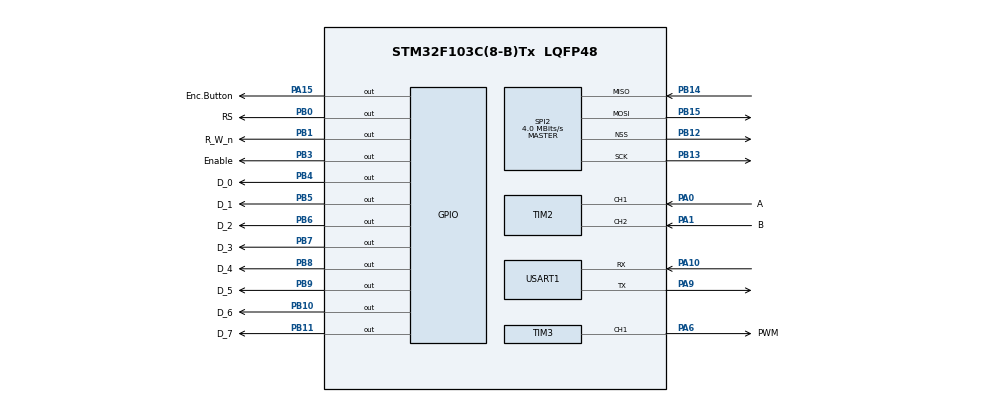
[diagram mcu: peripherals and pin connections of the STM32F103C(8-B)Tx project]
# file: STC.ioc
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Mcu.Family=STM32F1
Mcu.Name=STM32F103C(8-B)Tx
Mcu.Package=LQFP48
NVIC.PriorityGroup=NVIC_PRIORITYGROUP_4
PA0-WKUP.GPIO_Label=A
PA0-WKUP.Signal=S_TIM2_CH1_ETR
PA1.GPIO_Label=B
PA1.Signal=S_TIM2_CH2
PA10.Mode=Asynchronous
PA10.Signal=USART1_RX
PA13.Mode=Serial_Wire
PA13.Signal=SYS_JTMS-SWDIO
PA14.Mode=Serial_Wire
PA14.Signal=SYS_JTCK-SWCLK
PA15.GPIO_Label=Enc.Button
PA15.Signal=GPIO_Output
PA6.GPIO_Label=PWM
PA6.Signal=S_TIM3_CH1
PA9.Mode=Asynchronous
PA9.Signal=USART1_TX
PB0.GPIO_Label=RS
PB0.Signal=GPIO_Output
PB1.GPIO_Label=R_W_n
PB1.Signal=GPIO_Output
PB10.GPIO_Label=D_6
PB10.Signal=GPIO_Output
PB11.GPIO_Label=D_7
PB11.Signal=GPIO_Output
PB12.Mode=NSS_Signal_Hard_Output
PB12.Signal=SPI2_NSS
PB13.Mode=Full_Duplex_Master
PB13.Signal=SPI2_SCK
PB14.Mode=Full_Duplex_Master
PB14.Signal=SPI2_MISO
PB15.Mode=Full_Duplex_Master
PB15.Signal=SPI2_MOSI
PB3.GPIO_Label=Enable
PB3.Signal=GPIO_Output
PB4.GPIO_Label=D_0
PB4.Signal=GPIO_Output
PB5.GPIO_Label=D_1
PB5.Signal=GPIO_Output
PB6.GPIO_Label=D_2
PB6.Signal=GPIO_Output
PB7.GPIO_Label=D_3
PB7.Signal=GPIO_Output
PB8.GPIO_Label=D_4
PB8.Signal=GPIO_Output
PB9.GPIO_Label=D_5
PB9.Signal=GPIO_Output
PD0-OSC_IN.Mode=HSE-External-Clock-Source
PD0-OSC_IN.Signal=RCC_OSC_IN
PD1-OSC_OUT.Mode=HSE-External-Clock-Source
PD1-OSC_OUT.Signal=RCC_OSC_OUT
ProjectManager.HeapSize=0x200
ProjectManager.StackSize=0x400
ProjectManager.TargetToolchain=MDK-ARM V5.27
RCC.APB1Freq_Value=8000000
RCC.APB2Freq_Value=8000000
SH.S_TIM2_CH1_ETR.0=TIM2_CH1,Encoder_Interface
SH.S_TIM2_CH2.0=TIM2_CH2,Encoder_Interface
SH.S_TIM3_CH1.0=TIM3_CH1,PWM Generation1 CH1
SPI2.CalculateBaudRate=4.0 MBits/s
SPI2.Direction=SPI_DIRECTION_2LINES
SPI2.Mode=SPI_MODE_MASTER
SPI2.VirtualNSS=VM_NSSHARD
SPI2.VirtualType=VM_MASTER
TIM2.IC1Filter=10
TIM2.IC1Polarity=TIM_ICPOLARITY_FALLING
TIM2.IC2Filter=10
TIM2.IC2Polarity=TIM_ICPOLARITY_FALLING
TIM3.Channel-PWM\ Generation1\ CH1=TIM_CHANNEL_1
TIM3.Period=10000
TIM3.Prescaler=71
TIM3.Pulse-PWM\ Generation1\ CH1=100
USART1.VirtualMode=VM_ASYNC
VP_TIM3_VS_ClockSourceINT.Mode=Internal
board=custom

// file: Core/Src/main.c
/* USER CODE BEGIN Header */
/**
  ******************************************************************************
  * @file           : main.c
  * @brief          : Main program body
  ******************************************************************************
  * @attention
  *
  * <h2><center>&copy; Copyright (c) 2021 STMicroelectronics.
  * All rights reserved.</center></h2>
  *
  * This software component is licensed by ST under BSD 3-Clause license,
  * the "License"; You may not use this file except in compliance with the
  * License. You may obtain a copy of the License at:
  *                        opensource.org/licenses/BSD-3-Clause
  *
  ******************************************************************************
  */
/* USER CODE END Header */
#include "main.h"

SPI_HandleTypeDef hspi2;

TIM_HandleTypeDef htim2;
TIM_HandleTypeDef htim3;

UART_HandleTypeDef huart1;

/* USER CODE BEGIN PV */
uint8_t lcd_data;
/* USER CODE END PV */

void SystemClock_Config(void);
static void MX_GPIO_Init(void);
static void MX_TIM2_Init(void);
static void MX_USART1_UART_Init(void);
static void MX_SPI2_Init(void);
static void MX_TIM3_Init(void);

int main(void)
{

  /* MCU Configuration--------------------------------------------------------*/

  /* Reset of all peripherals, Initializes the Flash interface and the Systick. */
  HAL_Init();

  /* Configure the system clock */
  SystemClock_Config();

  /* Initialize all configured peripherals */
  MX_GPIO_Init();
  MX_TIM2_Init();
  MX_USART1_UART_Init();
  MX_SPI2_Init();
  MX_TIM3_Init();
  /* USER CODE BEGIN 2 */

  // LCD Initialization
  usr_lcd_init();
  lcd_data = 0x01;
  HAL_TIM_Base_Start_IT(&htim3);

  /* USER CODE END 2 */

  /* Infinite loop */
  /* USER CODE BEGIN WHILE */
  while (1)
  {

	  HAL_Delay(50);
	  //usr_lcd_init();
    /* USER CODE END WHILE */

  }
}

void SystemClock_Config(void)
{
  RCC_OscInitTypeDef RCC_OscInitStruct = {0};
  RCC_ClkInitTypeDef RCC_ClkInitStruct = {0};

  /** Initializes the RCC Oscillators according to the specified parameters
  * in the RCC_OscInitTypeDef structure.
  */
  RCC_OscInitStruct.OscillatorType = RCC_OSCILLATORTYPE_HSE;
  RCC_OscInitStruct.HSEState = RCC_HSE_ON;
  RCC_OscInitStruct.HSEPredivValue = RCC_HSE_PREDIV_DIV1;
  RCC_OscInitStruct.HSIState = RCC_HSI_ON;
  RCC_OscInitStruct.PLL.PLLState = RCC_PLL_ON;
  RCC_OscInitStruct.PLL.PLLSource = RCC_PLLSOURCE_HSE;
  RCC_OscInitStruct.PLL.PLLMUL = RCC_PLL_MUL9;
  if (HAL_RCC_OscConfig(&RCC_OscInitStruct) != HAL_OK)
  {
    Error_Handler();
  }
  /** Initializes the CPU, AHB and APB buses clocks
  */
  RCC_ClkInitStruct.ClockType = RCC_CLOCKTYPE_HCLK|RCC_CLOCKTYPE_SYSCLK
                              |RCC_CLOCKTYPE_PCLK1|RCC_CLOCKTYPE_PCLK2;
  RCC_ClkInitStruct.SYSCLKSource = RCC_SYSCLKSOURCE_PLLCLK;
  RCC_ClkInitStruct.AHBCLKDivider = RCC_SYSCLK_DIV1;
  RCC_ClkInitStruct.APB1CLKDivider = RCC_HCLK_DIV2;
  RCC_ClkInitStruct.APB2CLKDivider = RCC_HCLK_DIV1;

  if (HAL_RCC_ClockConfig(&RCC_ClkInitStruct, FLASH_LATENCY_2) != HAL_OK)
  {
    Error_Handler();
  }
}

static void MX_SPI2_Init(void)
{

  /* SPI2 parameter configuration*/
  hspi2.Instance = SPI2;
  hspi2.Init.Mode = SPI_MODE_MASTER;
  hspi2.Init.Direction = SPI_DIRECTION_2LINES;
  hspi2.Init.DataSize = SPI_DATASIZE_16BIT;
  hspi2.Init.CLKPolarity = SPI_POLARITY_LOW;
  hspi2.Init.CLKPhase = SPI_PHASE_1EDGE;
  hspi2.Init.NSS = SPI_NSS_SOFT;
  hspi2.Init.BaudRatePrescaler = SPI_BAUDRATEPRESCALER_256;
  hspi2.Init.FirstBit = SPI_FIRSTBIT_MSB;
  hspi2.Init.TIMode = SPI_TIMODE_DISABLE;
  hspi2.Init.CRCCalculation = SPI_CRCCALCULATION_DISABLE;
  hspi2.Init.CRCPolynomial = 10;
  if (HAL_SPI_Init(&hspi2) != HAL_OK)
  {
    Error_Handler();
  }

}

static void MX_TIM2_Init(void)
{

  TIM_MasterConfigTypeDef sMasterConfig = {0};
  TIM_OC_InitTypeDef sConfigOC = {0};

  htim2.Instance = TIM2;
  htim2.Init.Prescaler = 65535;
  htim2.Init.CounterMode = TIM_COUNTERMODE_UP;
  htim2.Init.Period = 65535;
  htim2.Init.ClockDivision = TIM_CLOCKDIVISION_DIV1;
  htim2.Init.AutoReloadPreload = TIM_AUTORELOAD_PRELOAD_DISABLE;
  if (HAL_TIM_PWM_Init(&htim2) != HAL_OK)
  {
    Error_Handler();
  }
  sMasterConfig.MasterOutputTrigger = TIM_TRGO_RESET;
  sMasterConfig.MasterSlaveMode = TIM_MASTERSLAVEMODE_DISABLE;
  if (HAL_TIMEx_MasterConfigSynchronization(&htim2, &sMasterConfig) != HAL_OK)
  {
    Error_Handler();
  }
  sConfigOC.OCMode = TIM_OCMODE_PWM1;
  sConfigOC.Pulse = 0;
  sConfigOC.OCPolarity = TIM_OCPOLARITY_HIGH;
  sConfigOC.OCFastMode = TIM_OCFAST_DISABLE;
  if (HAL_TIM_PWM_ConfigChannel(&htim2, &sConfigOC, TIM_CHANNEL_1) != HAL_OK)
  {
    Error_Handler();
  }
  HAL_TIM_MspPostInit(&htim2);

}

static void MX_TIM3_Init(void)
{

  TIM_MasterConfigTypeDef sMasterConfig = {0};
  TIM_OC_InitTypeDef sConfigOC = {0};

  htim3.Instance = TIM3;
  htim3.Init.Prescaler = 7199;
  htim3.Init.CounterMode = TIM_COUNTERMODE_UP;
  htim3.Init.Period = PERIOD;
  htim3.Init.ClockDivision = TIM_CLOCKDIVISION_DIV1;
  htim3.Init.AutoReloadPreload = TIM_AUTORELOAD_PRELOAD_DISABLE;
  if (HAL_TIM_PWM_Init(&htim3) != HAL_OK)
  {
    Error_Handler();
  }
  sMasterConfig.MasterOutputTrigger = TIM_TRGO_RESET;
  sMasterConfig.MasterSlaveMode = TIM_MASTERSLAVEMODE_DISABLE;
  if (HAL_TIMEx_MasterConfigSynchronization(&htim3, &sMasterConfig) != HAL_OK)
  {
    Error_Handler();
  }
  sConfigOC.OCMode = TIM_OCMODE_PWM1;
  sConfigOC.Pulse = PERIOD/2;
  sConfigOC.OCPolarity = TIM_OCPOLARITY_HIGH;
  sConfigOC.OCFastMode = TIM_OCFAST_DISABLE;
  if (HAL_TIM_PWM_ConfigChannel(&htim3, &sConfigOC, TIM_CHANNEL_3) != HAL_OK)
  {
    Error_Handler();
  }

}

static void MX_USART1_UART_Init(void)
{

  huart1.Instance = USART1;
  huart1.Init.BaudRate = 115200;
  huart1.Init.WordLength = UART_WORDLENGTH_8B;
  huart1.Init.StopBits = UART_STOPBITS_1;
  huart1.Init.Parity = UART_PARITY_NONE;
  huart1.Init.Mode = UART_MODE_TX_RX;
  huart1.Init.HwFlowCtl = UART_HWCONTROL_NONE;
  huart1.Init.OverSampling = UART_OVERSAMPLING_16;
  if (HAL_UART_Init(&huart1) != HAL_OK)
  {
    Error_Handler();
  }

}

static void MX_GPIO_Init(void)
{
  GPIO_InitTypeDef GPIO_InitStruct = {0};

  /* GPIO Ports Clock Enable */
  __HAL_RCC_GPIOC_CLK_ENABLE();
  __HAL_RCC_GPIOD_CLK_ENABLE();
  __HAL_RCC_GPIOA_CLK_ENABLE();
  __HAL_RCC_GPIOB_CLK_ENABLE();

  /*Configure GPIO pin Output Level */
  HAL_GPIO_WritePin(LED_GPIO_Port, LED_Pin, GPIO_PIN_RESET);

  /*Configure GPIO pin Output Level */
  HAL_GPIO_WritePin(GPIOB, lcd_rs_Pin|lcd_rw_Pin|lcd_d6_Pin|lcd_d7_Pin
                          |SPI2_NSS_Pin|lcd_en_Pin|lcd_d0_Pin|lcd_d1_Pin
                          |lcd_d2_Pin|lcd_d3_Pin|lcd_d4_Pin|lcd_d5_Pin, GPIO_PIN_RESET);

  /*Configure GPIO pin : LED_Pin */
  GPIO_InitStruct.Pin = LED_Pin;
  GPIO_InitStruct.Mode = GPIO_MODE_OUTPUT_PP;
  GPIO_InitStruct.Pull = GPIO_NOPULL;
  GPIO_InitStruct.Speed = GPIO_SPEED_FREQ_LOW;
  HAL_GPIO_Init(LED_GPIO_Port, &GPIO_InitStruct);

  /*Configure GPIO pins : lcd_rs_Pin lcd_rw_Pin lcd_d6_Pin lcd_d7_Pin
                           SPI2_NSS_Pin lcd_en_Pin lcd_d0_Pin lcd_d1_Pin
                           lcd_d2_Pin lcd_d3_Pin lcd_d4_Pin lcd_d5_Pin */
  GPIO_InitStruct.Pin = lcd_rs_Pin|lcd_rw_Pin|lcd_d6_Pin|lcd_d7_Pin
                          |SPI2_NSS_Pin|lcd_en_Pin|lcd_d0_Pin|lcd_d1_Pin
                          |lcd_d2_Pin|lcd_d3_Pin|lcd_d4_Pin|lcd_d5_Pin;
  GPIO_InitStruct.Mode = GPIO_MODE_OUTPUT_PP;
  GPIO_InitStruct.Pull = GPIO_NOPULL;
  GPIO_InitStruct.Speed = GPIO_SPEED_FREQ_LOW;
  HAL_GPIO_Init(GPIOB, &GPIO_InitStruct);

}

/* USER CODE BEGIN 4 */
void usr_lcd_init(void)
{
	HAL_GPIO_WritePin(lcd_en_GPIO_Port, lcd_en_Pin, GPIO_PIN_RESET);
	HAL_GPIO_WritePin(lcd_rw_GPIO_Port, lcd_rw_Pin, GPIO_PIN_RESET);
	HAL_Delay(15);
	usr_lcd_write((uint8_t) 0x30 , (uint8_t) 0x00);
	HAL_Delay(5);
	usr_lcd_write((uint8_t) 0x30 , (uint8_t) 0x00);
	HAL_Delay(1);
	usr_lcd_write((uint8_t) 0x30 , (uint8_t) 0x00);
	HAL_Delay(1);
	usr_lcd_write((uint8_t) 0x38 , (uint8_t) 0x00);
	HAL_Delay(1);
	usr_lcd_write((uint8_t) 0x08 , (uint8_t) 0x00);
	HAL_Delay(1);
	usr_lcd_write((uint8_t) 0x01 , (uint8_t) 0x00);
	HAL_Delay(2);
	usr_lcd_write((uint8_t) 0x02 , (uint8_t) 0x00);
	HAL_Delay(1);
	usr_lcd_write((uint8_t) 0x0F , (uint8_t) 0x00);
	HAL_Delay(1);

}

void usr_lcd_write(uint8_t data, uint8_t reg_sel)
{
	char temp;
	if (reg_sel) {
		HAL_GPIO_WritePin(lcd_rs_GPIO_Port, lcd_rs_Pin, GPIO_PIN_SET);
	} else {
		HAL_GPIO_WritePin(lcd_rs_GPIO_Port, lcd_rs_Pin, GPIO_PIN_RESET);
	}
	temp = data & (0x01 << 0);
	if (temp){
		HAL_GPIO_WritePin(lcd_d0_GPIO_Port, lcd_d0_Pin, GPIO_PIN_SET);
	} else {
		HAL_GPIO_WritePin(lcd_d0_GPIO_Port, lcd_d0_Pin, GPIO_PIN_RESET);
	}
	temp = data & (0x01 << 1);
	if (temp){
		HAL_GPIO_WritePin(lcd_d1_GPIO_Port, lcd_d1_Pin, GPIO_PIN_SET);
	} else {
		HAL_GPIO_WritePin(lcd_d1_GPIO_Port, lcd_d1_Pin, GPIO_PIN_RESET);
	}
	temp = data & (0x01 << 2);
	if (temp){
		HAL_GPIO_WritePin(lcd_d2_GPIO_Port, lcd_d2_Pin, GPIO_PIN_SET);
	} else {
		HAL_GPIO_WritePin(lcd_d2_GPIO_Port, lcd_d2_Pin, GPIO_PIN_RESET);
	}
	temp = data & (0x01 << 3);
	if (temp){
		HAL_GPIO_WritePin(lcd_d3_GPIO_Port, lcd_d3_Pin, GPIO_PIN_SET);
	} else {
		HAL_GPIO_WritePin(lcd_d3_GPIO_Port, lcd_d3_Pin, GPIO_PIN_RESET);
	}
	temp = data & (0x01 << 4);
	if (temp){
		HAL_GPIO_WritePin(lcd_d4_GPIO_Port, lcd_d4_Pin, GPIO_PIN_SET);
	} else {
		HAL_GPIO_WritePin(lcd_d4_GPIO_Port, lcd_d4_Pin, GPIO_PIN_RESET);
	}
	temp = data & (0x01 << 5);
	if (temp){
		HAL_GPIO_WritePin(lcd_d5_GPIO_Port, lcd_d5_Pin, GPIO_PIN_SET);
	} else {
		HAL_GPIO_WritePin(lcd_d5_GPIO_Port, lcd_d5_Pin, GPIO_PIN_RESET);
	}
	temp = data & (0x01 << 6);
	if (temp){
		HAL_GPIO_WritePin(lcd_d6_GPIO_Port, lcd_d6_Pin, GPIO_PIN_SET);
	} else {
		HAL_GPIO_WritePin(lcd_d6_GPIO_Port, lcd_d6_Pin, GPIO_PIN_RESET);
	}
	temp = data & (0x01 << 7);
	if (temp){
		HAL_GPIO_WritePin(lcd_d7_GPIO_Port, lcd_d7_Pin, GPIO_PIN_SET);
	} else {
		HAL_GPIO_WritePin(lcd_d7_GPIO_Port, lcd_d7_Pin, GPIO_PIN_RESET);
	}
	HAL_Delay(1);
	HAL_GPIO_WritePin(lcd_en_GPIO_Port, lcd_en_Pin, GPIO_PIN_SET);
	HAL_Delay(1);
	HAL_GPIO_WritePin(lcd_en_GPIO_Port, lcd_en_Pin, GPIO_PIN_RESET);
}
/* USER CODE END 4 */

void Error_Handler(void)
{
  __disable_irq();
  while (1)
  {
  }
}

/************************ (C) COPYRIGHT STMicroelectronics *****END OF FILE****/
